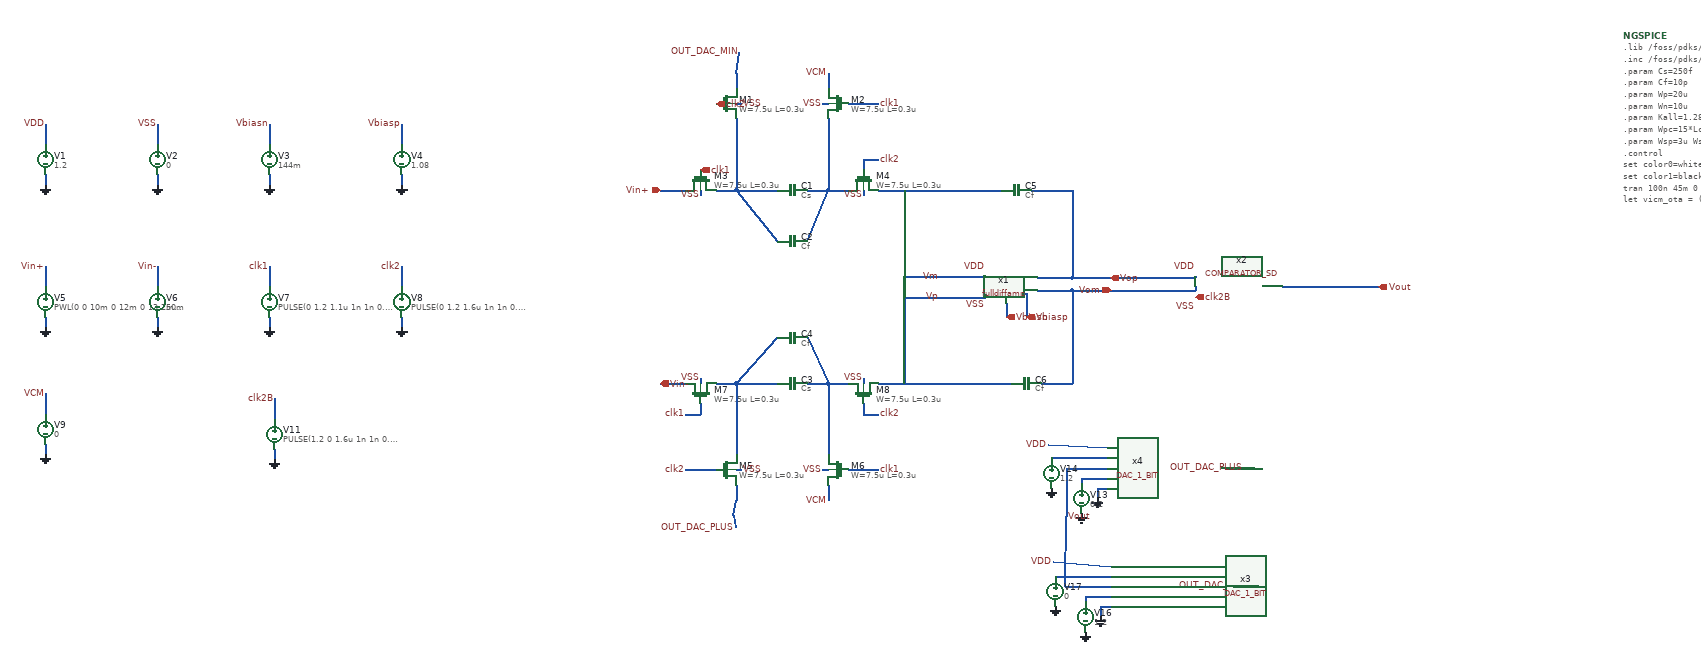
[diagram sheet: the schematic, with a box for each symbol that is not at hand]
v {xschem version=3.4.8RC file_version=1.3}
G {}
K {}
V {}
S {}
F {}
E {}
N 347.5 -1320 347.5 -1180 {lab=#net1}
N 307.5 -1180 347.5 -1180 {lab=#net1}
N 347.5 -1180 427.5 -1180 {lab=#net1}
N 487.5 -1180 527.5 -1180 {lab=#net2}
N 527.5 -1320 527.5 -1180 {lab=#net2}
N 527.5 -1180 567.5 -1180 {lab=#net2}
N 627.5 -1180 667.5 -1180 {lab=Vm}
N 227.5 -1180 247.5 -1180 {lab=Vin+}
N 197.5 -1180 227.5 -1180 {lab=Vin+}
N 597.5 -1240 597.5 -1220 {lab=clk2}
N 597.5 -1240 627.5 -1240 {lab=clk2}
N 567.5 -1350 627.5 -1350 {lab=clk1}
N 527.5 -1410 527.5 -1380 {lab=VCM}
N 347.5 -1410 347.5 -1380 {lab=OUT_DAC_MIN}
N 347.5 -800 347.5 -660 {lab=#net3}
N 307.5 -800 347.5 -800 {lab=#net3}
N 347.5 -800 427.5 -800 {lab=#net3}
N 487.5 -800 527.5 -800 {lab=#net4}
N 527.5 -800 527.5 -660 {lab=#net4}
N 527.5 -800 567.5 -800 {lab=#net4}
N 627.5 -800 667.5 -800 {lab=Vp}
N 227.5 -800 247.5 -800 {lab=Vin-}
N 197.5 -800 227.5 -800 {lab=Vin-}
N 277.5 -760 277.5 -740 {lab=clk1}
N 247.5 -740 277.5 -740 {lab=clk1}
N 247.5 -630 307.5 -630 {lab=clk2}
N 597.5 -760 597.5 -740 {lab=clk2}
N 597.5 -740 627.5 -740 {lab=clk2}
N 567.5 -630 627.5 -630 {lab=clk1}
N 527.5 -600 527.5 -570 {lab=VCM}
N 347.5 -600 347.5 -570 {lab=OUT_DAC_PLUS}
N 347.5 -1350 357.5 -1350 {lab=VSS}
N 517.5 -1350 527.5 -1350 {lab=VSS}
N 277.5 -1180 277.5 -1170 {lab=VSS}
N 597.5 -1180 597.5 -1170 {lab=VSS}
N 277.5 -810 277.5 -800 {lab=VSS}
N 597.5 -810 597.5 -800 {lab=VSS}
N 347.5 -630 357.5 -630 {lab=VSS}
N 517.5 -630 527.5 -630 {lab=VSS}
N 667.5 -1180 867.5 -1180 {lab=Vm}
N 667.5 -800 887.5 -800 {lab=Vp}
N 677.5 -1180 677.5 -1010 {lab=Vm}
N 677.5 -1010 837.5 -1010 {lab=Vm}
N 677.5 -970 677.5 -800 {lab=Vp}
N 677.5 -970 837.5 -970 {lab=Vp}
N 837.5 -975 837.5 -970 {lab=Vp}
N 927.5 -1180 997.5 -1180 {lab=Vop}
N 947.5 -800 1007.5 -800 {lab=Vom}
N 940 -983.75 1007.5 -983.75 {lab=Vom}
N 938.75 -1007.5 1006.25 -1007.5 {lab=Vop}
N 997.5 -1180 1007.5 -1180 {lab=Vop}
N 1006.25 -1007.5 1007.5 -1007.5 {lab=Vop}
N 1007.5 -1180 1007.5 -1007.5 {lab=Vop}
N 1007.5 -983.75 1007.5 -800 {lab=Vom}
N 910 -977.5 917.5 -977.5 {lab=Vbiasp}
N 917.5 -977.5 917.5 -930 {lab=Vbiasp}
N 877.5 -957.5 877.5 -930 {lab=Vbiasn}
N 1007.5 -1007.5 1050 -1007.5 {lab=Vop}
N 1007.5 -983.75 1050 -983.75 {lab=Vom}
N 1052.5 -1007.5 1100 -1007.5 {lab=Vop}
N 1052.5 -983.75 1100 -983.75 {lab=Vom}
N 1050 -1007.5 1052.5 -1007.5 {lab=Vop}
N 1050 -983.75 1052.5 -983.75 {lab=Vom}
N -1010 -1310 -1010 -1270 {lab=VDD}
N -1010 -1210 -1010 -1190 {lab=0}
N -790 -1310 -790 -1270 {lab=VSS}
N -790 -1210 -790 -1190 {lab=0}
N -570 -1310 -570 -1270 {lab=Vbiasn}
N -570 -1210 -570 -1190 {lab=0}
N -310 -1310 -310 -1270 {lab=Vbiasp}
N -310 -1210 -310 -1190 {lab=0}
N -1010 -1030 -1010 -990 {lab=Vin+}
N -1010 -930 -1010 -910 {lab=0}
N -790 -1030 -790 -990 {lab=Vin-}
N -790 -930 -790 -910 {lab=0}
N -570 -1030 -570 -990 {lab=clk1}
N -570 -930 -570 -910 {lab=0}
N -310 -1030 -310 -990 {lab=clk2}
N -310 -930 -310 -910 {lab=0}
N -1010 -780 -1010 -740 {lab=VCM}
N -1010 -680 -1010 -660 {lab=0}
N 347.5 -1180 427.5 -1080 {lab=#net1}
N 487.5 -1080 527.5 -1180 {lab=#net2}
N 347.5 -800 427.5 -890 {lab=#net3}
N 487.5 -890 527.5 -800 {lab=#net4}
N -560 -770 -560 -730 {lab=clk2B}
N -560 -670 -560 -650 {lab=0}
N 342.5 -540 347.5 -570 {lab=OUT_DAC_PLUS}
N 1100 -1007.5 1250 -1007.5 {lab=Vop}
N 1250 -1010 1250 -1007.5 {lab=Vop}
N 1100 -983.75 1250 -983.75 {lab=Vom}
N 1250 -990 1250 -983.75 {lab=Vom}
N 1420 -990 1590 -990 {lab=Vout}
N 1590 -990 1610 -990 {lab=Vout}
N 1026.25 -613.75 1076.25 -613.75 {lab=#net5}
N 1026.25 -613.75 1026.25 -603.75 {lab=#net5}
N 996.25 -633.75 1076.25 -633.75 {lab=Vout}
N 996.25 -633.75 996.25 -538.75 {lab=Vout}
N 1056.25 -593.75 1076.25 -593.75 {lab=0}
N 1056.25 -593.75 1056.25 -573.75 {lab=0}
N 966.25 -653.75 1076.25 -653.75 {lab=#net6}
N 1033.75 -381.25 1083.75 -381.25 {lab=#net7}
N 1033.75 -381.25 1033.75 -371.25 {lab=#net7}
N 1003.75 -401.25 1083.75 -401.25 {lab=Vout}
N 1063.75 -361.25 1083.75 -361.25 {lab=0}
N 1063.75 -361.25 1063.75 -341.25 {lab=0}
N 973.75 -421.25 1083.75 -421.25 {lab=#net8}
N 1323.75 -401.25 1373.75 -401.25 {lab=OUT_DAC_MIN}
N 1002.5 -401.25 1003.75 -401.25 {lab=Vout}
N 993.75 -401.25 1002.5 -401.25 {lab=Vout}
N 993.75 -401.25 996.25 -538.75 {lab=Vout}
N 1315 -633.75 1366.25 -633.75 {lab=OUT_DAC_PLUS}
N 347.5 -1410 353.75 -1451.25 {lab=OUT_DAC_MIN}
N 342.5 -540 345.625 -516.25 {lab=OUT_DAC_PLUS}
N 960 -680 1076.25 -673.75 {lab=VDD}
N 970 -450 1083.75 -441.25 {lab=VDD}
C {symbols/nfet_03v3.sym} 327.5 -1350 2 1 {name=M1
L=0.3u
W=7.5u
nf=1
m=1
ad="'int((nf+1)/2) * W/nf * 0.18u'"
pd="'2*int((nf+1)/2) * (W/nf + 0.18u)'"
as="'int((nf+2)/2) * W/nf * 0.18u'"
ps="'2*int((nf+2)/2) * (W/nf + 0.18u)'"
nrd="'0.18u / W'" nrs="'0.18u / W'"
sa=0 sb=0 sd=0
model=nfet_03v3
spiceprefix=X
}
C {symbols/nfet_03v3.sym} 547.5 -1350 2 0 {name=M2
L=0.3u
W=7.5u
nf=1
m=1
ad="'int((nf+1)/2) * W/nf * 0.18u'"
pd="'2*int((nf+1)/2) * (W/nf + 0.18u)'"
as="'int((nf+2)/2) * W/nf * 0.18u'"
ps="'2*int((nf+2)/2) * (W/nf + 0.18u)'"
nrd="'0.18u / W'" nrs="'0.18u / W'"
sa=0 sb=0 sd=0
model=nfet_03v3
spiceprefix=X
}
C {symbols/nfet_03v3.sym} 277.5 -1200 3 1 {name=M3
L=0.3u
W=7.5u
nf=1
m=1
ad="'int((nf+1)/2) * W/nf * 0.18u'"
pd="'2*int((nf+1)/2) * (W/nf + 0.18u)'"
as="'int((nf+2)/2) * W/nf * 0.18u'"
ps="'2*int((nf+2)/2) * (W/nf + 0.18u)'"
nrd="'0.18u / W'" nrs="'0.18u / W'"
sa=0 sb=0 sd=0
model=nfet_03v3
spiceprefix=X
}
C {symbols/nfet_03v3.sym} 597.5 -1200 3 1 {name=M4
L=0.3u
W=7.5u
nf=1
m=1
ad="'int((nf+1)/2) * W/nf * 0.18u'"
pd="'2*int((nf+1)/2) * (W/nf + 0.18u)'"
as="'int((nf+2)/2) * W/nf * 0.18u'"
ps="'2*int((nf+2)/2) * (W/nf + 0.18u)'"
nrd="'0.18u / W'" nrs="'0.18u / W'"
sa=0 sb=0 sd=0
model=nfet_03v3
spiceprefix=X
}
C {capa.sym} 457.5 -1180 1 1 {name=C1
m=1
value=Cs
footprint=1206
device="ceramic capacitor"}
C {ipin.sym} 197.5 -1180 0 0 {name=p3 lab=Vin+}
C {lab_pin.sym} 627.5 -1350 2 0 {name=p1 sig_type=std_logic lab=clk1}
C {lab_pin.sym} 627.5 -1240 2 0 {name=p5 sig_type=std_logic lab=clk2}
C {symbols/nfet_03v3.sym} 327.5 -630 0 0 {name=M5
L=0.3u
W=7.5u
nf=1
m=1
ad="'int((nf+1)/2) * W/nf * 0.18u'"
pd="'2*int((nf+1)/2) * (W/nf + 0.18u)'"
as="'int((nf+2)/2) * W/nf * 0.18u'"
ps="'2*int((nf+2)/2) * (W/nf + 0.18u)'"
nrd="'0.18u / W'" nrs="'0.18u / W'"
sa=0 sb=0 sd=0
model=nfet_03v3
spiceprefix=X
}
C {symbols/nfet_03v3.sym} 547.5 -630 0 1 {name=M6
L=0.3u
W=7.5u
nf=1
m=1
ad="'int((nf+1)/2) * W/nf * 0.18u'"
pd="'2*int((nf+1)/2) * (W/nf + 0.18u)'"
as="'int((nf+2)/2) * W/nf * 0.18u'"
ps="'2*int((nf+2)/2) * (W/nf + 0.18u)'"
nrd="'0.18u / W'" nrs="'0.18u / W'"
sa=0 sb=0 sd=0
model=nfet_03v3
spiceprefix=X
}
C {symbols/nfet_03v3.sym} 277.5 -780 3 0 {name=M7
L=0.3u
W=7.5u
nf=1
m=1
ad="'int((nf+1)/2) * W/nf * 0.18u'"
pd="'2*int((nf+1)/2) * (W/nf + 0.18u)'"
as="'int((nf+2)/2) * W/nf * 0.18u'"
ps="'2*int((nf+2)/2) * (W/nf + 0.18u)'"
nrd="'0.18u / W'" nrs="'0.18u / W'"
sa=0 sb=0 sd=0
model=nfet_03v3
spiceprefix=X
}
C {symbols/nfet_03v3.sym} 597.5 -780 3 0 {name=M8
L=0.3u
W=7.5u
nf=1
m=1
ad="'int((nf+1)/2) * W/nf * 0.18u'"
pd="'2*int((nf+1)/2) * (W/nf + 0.18u)'"
as="'int((nf+2)/2) * W/nf * 0.18u'"
ps="'2*int((nf+2)/2) * (W/nf + 0.18u)'"
nrd="'0.18u / W'" nrs="'0.18u / W'"
sa=0 sb=0 sd=0
model=nfet_03v3
spiceprefix=X
}
C {capa.sym} 457.5 -800 1 0 {name=C3
m=1
value=Cs
footprint=1206
device="ceramic capacitor"}
C {ipin.sym} 197.5 -800 2 1 {name=p6 lab=Vin-}
C {lab_pin.sym} 627.5 -630 0 1 {name=p7 sig_type=std_logic lab=clk1}
C {lab_pin.sym} 247.5 -740 2 1 {name=p8 sig_type=std_logic lab=clk1}
C {lab_pin.sym} 247.5 -630 2 1 {name=p9 sig_type=std_logic lab=clk2}
C {lab_pin.sym} 627.5 -740 0 1 {name=p10 sig_type=std_logic lab=clk2}
C {lab_pin.sym} 357.5 -1350 2 0 {name=p13 sig_type=std_logic lab=VSS}
C {lab_pin.sym} 517.5 -1350 0 0 {name=p14 sig_type=std_logic lab=VSS}
C {lab_pin.sym} 277.5 -1170 3 0 {name=p15 sig_type=std_logic lab=VSS}
C {lab_pin.sym} 597.5 -1170 3 0 {name=p16 sig_type=std_logic lab=VSS}
C {lab_pin.sym} 277.5 -810 1 0 {name=p17 sig_type=std_logic lab=VSS}
C {lab_pin.sym} 597.5 -810 1 0 {name=p18 sig_type=std_logic lab=VSS}
C {lab_pin.sym} 357.5 -630 2 0 {name=p19 sig_type=std_logic lab=VSS}
C {lab_pin.sym} 517.5 -630 0 0 {name=p20 sig_type=std_logic lab=VSS}
C {capa.sym} 897.5 -1180 3 0 {name=C5
m=1
value=Cf
footprint=1206
device="ceramic capacitor"}
C {capa.sym} 917.5 -800 3 0 {name=C6
m=1
value=Cf
footprint=1206
device="ceramic capacitor"}
C {opin.sym} 1082.5 -1007.5 3 0 {name=p11 lab=Vop}
C {opin.sym} 1083.75 -983.75 3 1 {name=p12 lab=Vom}
C {lab_pin.sym} 837.5 -955 0 0 {name=p23 sig_type=std_logic lab=VSS}
C {lab_pin.sym} 837.5 -1030 0 0 {name=p24 sig_type=std_logic lab=VDD}
C {lab_pin.sym} 527.5 -570 3 0 {name=p38 sig_type=std_logic lab=VCM}
C {lab_pin.sym} 527.5 -1410 1 0 {name=p39 sig_type=std_logic lab=VCM}
C {ipin.sym} 277.5 -1220 3 1 {name=p41 lab=clk1}
C {ipin.sym} 307.5 -1350 2 1 {name=p2 lab=clk2}
C {ipin.sym} 877.5 -930 1 1 {name=p4 lab=Vbiasn}
C {ipin.sym} 917.5 -930 1 1 {name=p42 lab=Vbiasp}
C {lab_pin.sym} 747.5 -1010 1 0 {name=p33 sig_type=std_logic lab=Vm}
C {lab_pin.sym} 747.5 -970 3 0 {name=p34 sig_type=std_logic lab=Vp}
C {fulldiffamp.sym} 897.5 -905 0 0 {name=x1}
C {vsource.sym} -1010 -1240 0 0 {name=V1 value=1.2 savecurrent=false}
C {gnd.sym} -1010 -1190 0 0 {name=l5 lab=0}
C {vsource.sym} -790 -1240 0 0 {name=V2 value=0 savecurrent=false}
C {gnd.sym} -790 -1190 0 0 {name=l6 lab=0}
C {vsource.sym} -570 -1240 0 0 {name=V3 value=144m savecurrent=false}
C {gnd.sym} -570 -1190 0 0 {name=l7 lab=0}
C {vsource.sym} -310 -1240 0 0 {name=V4 value=1.08 savecurrent=false}
C {gnd.sym} -310 -1190 0 0 {name=l8 lab=0}
C {gnd.sym} -1010 -910 0 0 {name=l9 lab=0}
C {gnd.sym} -790 -910 0 0 {name=l10 lab=0}
C {vsource.sym} -570 -960 0 0 {name=V7 value="PULSE(0 1.2 1.1u 1n 1n 0.32u 1u)" savecurrent=false}
C {gnd.sym} -570 -910 0 0 {name=l11 lab=0}
C {vsource.sym} -310 -960 0 0 {name=V8 value="PULSE(0 1.2 1.6u 1n 1n 0.32u 1u)" savecurrent=false}
C {gnd.sym} -310 -910 0 0 {name=l12 lab=0}
C {lab_pin.sym} -1010 -1310 1 0 {name=p25 sig_type=std_logic lab=VDD}
C {lab_pin.sym} -790 -1310 1 0 {name=p26 sig_type=std_logic lab=VSS
}
C {lab_pin.sym} -570 -1310 1 0 {name=p27 sig_type=std_logic lab=Vbiasn
}
C {lab_pin.sym} -310 -1310 1 0 {name=p28 sig_type=std_logic lab=Vbiasp
}
C {lab_pin.sym} -1010 -1030 1 0 {name=p29 sig_type=std_logic lab=Vin+}
C {lab_pin.sym} -790 -1030 1 0 {name=p30 sig_type=std_logic lab=Vin-}
C {lab_pin.sym} -570 -1030 1 0 {name=p31 sig_type=std_logic lab=clk1}
C {lab_pin.sym} -310 -1030 1 0 {name=p32 sig_type=std_logic lab=clk2}
C {vsource.sym} -1010 -710 0 0 {name=V9 value=0 savecurrent=false}
C {gnd.sym} -1010 -660 0 0 {name=l1 lab=0}
C {lab_pin.sym} -1010 -780 1 0 {name=p35 sig_type=std_logic lab=VCM}
C {devices/code_shown.sym} 2091.25 -1483.75 0 0 {name=NGSPICE only_toplevel=true
value="
.lib /foss/pdks/gf180mcuD/libs.tech/ngspice/sm141064.ngspice typical
.inc /foss/pdks/gf180mcuD/libs.tech/ngspice/design.ngspice

.param Cs=250f
.param Cf=10p
.param Wp=20u
.param Wn=10u
.param Kall=1.28u
.param Wpc=15*Lc Wnc=2*Wpc Wsc=2*Wpc Lc=1.28u
.param Wsp=3u Wsn=1.5u Ld=0.3u Wdp=2u Wdn=1u

.control
set color0=white
set color1=black
tran 100n 45m 0 50n
let vicm_ota = (v(Vp)+v(Vm))/2
let vid_ota  = v(Vp)-v(Vm)
let vod = v(Vop)-v(Vom)
let vocm = (v(Vop)+v(Vom))/2
*plot v(clk1) v(clk2)
plot v(Vout) v(Vin+) v(Vin-)
plot v(Vin+) v(Vin-)
*plot v(Vop) v(Vom) v(Vin+) v(Vin-)
*plot v(Vp) v(Vm) v(Vin+) v(Vin-)
*plot v(Vout)
*plot v(OUT_DAC_PLUS) v(OUT_DAC_MIN)
*plot vod
*plot vocm
*plot vicm_ota
*plot vid_ota
write analog_integration_v4_debug.raw v(clk1) v(clk2) v(Vin+) v(Vin-) v(Vm) v(Vp) v(Vop) v(Vom)
.endc
.end
"}
C {capa.sym} 457.5 -1080 1 1 {name=C2
m=1
value=Cf
footprint=1206
device="ceramic capacitor"}
C {capa.sym} 457.5 -890 1 1 {name=C4
m=1
value=Cf
footprint=1206
device="ceramic capacitor"}
C {vsource.sym} -560 -700 0 0 {name=V11 value="PULSE(1.2 0 1.6u 1n 1n 0.32u 1u)" savecurrent=false}
C {gnd.sym} -560 -650 0 0 {name=l13 lab=0}
C {lab_pin.sym} -560 -770 1 0 {name=p49 sig_type=std_logic lab=clk2B}
C {/foss/designs/low-power-12b-first-order-delta-sigma-adc/src/schematics/latched_comparator/COMPARATOR_SD.sym} 1230 -830 0 0 {name=x2}
C {lab_pin.sym} 1250 -1030 0 0 {name=p46 sig_type=std_logic lab=VDD}
C {lab_pin.sym} 1250 -950 0 0 {name=p47 sig_type=std_logic lab=VSS}
C {ipin.sym} 1250 -970 2 1 {name=p57 lab=clk2B}
C {opin.sym} 1610 -990 0 0 {name=p64 lab=Vout}
C {gnd.sym} 1056.25 -573.75 0 0 {name=l21 lab=0}
C {vsource.sym} 1026.25 -573.75 0 0 {name=V13 value=0.2 savecurrent=false}
C {gnd.sym} 966.25 -593.75 0 0 {name=l22 lab=0}
C {vsource.sym} 966.25 -623.75 0 0 {name=V14 value=1.2 savecurrent=false}
C {gnd.sym} 1026.25 -543.75 0 0 {name=l24 lab=0}
C {gnd.sym} 1063.75 -341.25 0 0 {name=l26 lab=0}
C {vsource.sym} 1033.75 -341.25 0 0 {name=V16 value=1.2 savecurrent=false}
C {gnd.sym} 973.75 -361.25 0 0 {name=l27 lab=0}
C {lab_pin.sym} 1353.75 -401.25 1 0 {name=p60 sig_type=std_logic lab=OUT_DAC_MIN}
C {vsource.sym} 973.75 -391.25 0 0 {name=V17 value=0 savecurrent=false}
C {gnd.sym} 1033.75 -311.25 0 0 {name=l29 lab=0}
C {lab_pin.sym} 1344.375 -633.75 1 0 {name=p61 sig_type=std_logic lab=OUT_DAC_PLUS}
C {lab_pin.sym} 996.25 -538.75 2 0 {name=p62 sig_type=std_logic lab=Vout}
C {/foss/designs/low-power-12b-first-order-delta-sigma-adc/src/schematics/dac_1bit/DAC_1_BIT.sym} 1066.25 -573.75 0 0 {name=x4}
C {/foss/designs/low-power-12b-first-order-delta-sigma-adc/src/schematics/dac_1bit/DAC_1_BIT.sym} 1073.75 -341.25 0 0 {name=x3}
C {lab_pin.sym} 353.75 -1451.25 1 0 {name=p21 sig_type=std_logic lab=OUT_DAC_MIN}
C {lab_pin.sym} 345.625 -516.25 3 0 {name=p22 sig_type=std_logic lab=OUT_DAC_PLUS}
C {lab_pin.sym} 960 -680 0 0 {name=p36 sig_type=std_logic lab=VDD}
C {lab_pin.sym} 970 -450 0 0 {name=p37 sig_type=std_logic lab=VDD}
C {vsource.sym} -1010 -960 0 0 {name=V5 value="PWL(0 0 10m 0 12m 0 13.2m 54m 14.4m 0 17m 0 17.8m 21.6m 18m 270m 18.3m 10.8m 19m 0 22m 86.4m 24.4m 0 30m 0 32m 0 33.2m 54m 34.4m 0 37m 0 37.8m 21.6m 38m 270m 38.3m 10.8m 39m 0 42m 86.4m 44.4m 0 50m 0)" savecurrent=false}
C {vsource.sym} -790 -960 0 0 {name=V6 value=50m savecurrent=false}
